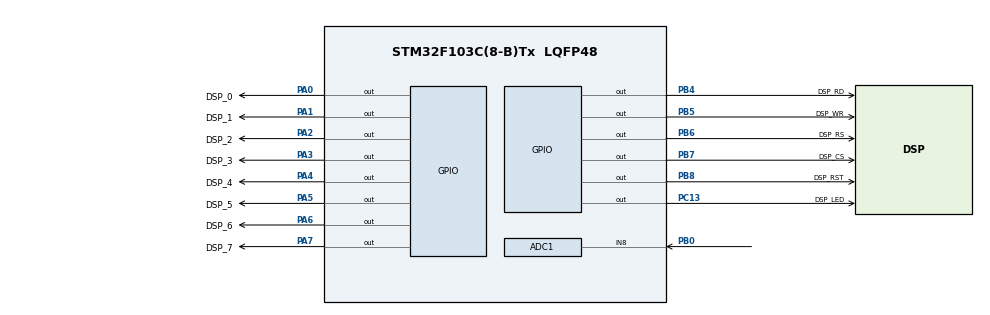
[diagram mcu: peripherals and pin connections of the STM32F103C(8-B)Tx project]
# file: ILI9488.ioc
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ADC1.Channel-0\#ChannelRegularConversion=ADC_CHANNEL_8
ADC1.ExternalTrigConv=ADC_EXTERNALTRIGCONV_T3_TRGO
ADC1.NbrOfConversionFlag=1
ADC1.Rank-0\#ChannelRegularConversion=1
ADC1.SamplingTime-0\#ChannelRegularConversion=ADC_SAMPLETIME_1CYCLE_5
ADC1.master=1
Mcu.Family=STM32F1
Mcu.Name=STM32F103C(8-B)Tx
Mcu.Package=LQFP48
NVIC.PriorityGroup=NVIC_PRIORITYGROUP_4
NVIC.TIM3_IRQn=true\:0\:0\:false\:false\:true
PA0-WKUP.GPIO_Label=DSP_0
PA0-WKUP.GPIO_ModeDefaultOutputPP=GPIO_MODE_OUTPUT_PP
PA0-WKUP.GPIO_Speed=GPIO_SPEED_FREQ_HIGH
PA0-WKUP.PinState=GPIO_PIN_RESET
PA0-WKUP.Signal=GPIO_Output
PA1.GPIO_Label=DSP_1
PA1.GPIO_ModeDefaultOutputPP=GPIO_MODE_OUTPUT_PP
PA1.GPIO_Speed=GPIO_SPEED_FREQ_HIGH
PA1.PinState=GPIO_PIN_RESET
PA1.Signal=GPIO_Output
PA13.Mode=Serial_Wire
PA13.Signal=SYS_JTMS-SWDIO
PA14.Mode=Serial_Wire
PA14.Signal=SYS_JTCK-SWCLK
PA2.GPIO_Label=DSP_2
PA2.GPIO_ModeDefaultOutputPP=GPIO_MODE_OUTPUT_PP
PA2.GPIO_Speed=GPIO_SPEED_FREQ_HIGH
PA2.PinState=GPIO_PIN_RESET
PA2.Signal=GPIO_Output
PA3.GPIO_Label=DSP_3
PA3.GPIO_ModeDefaultOutputPP=GPIO_MODE_OUTPUT_PP
PA3.GPIO_Speed=GPIO_SPEED_FREQ_HIGH
PA3.PinState=GPIO_PIN_RESET
PA3.Signal=GPIO_Output
PA4.GPIO_Label=DSP_4
PA4.GPIO_ModeDefaultOutputPP=GPIO_MODE_OUTPUT_PP
PA4.GPIO_Speed=GPIO_SPEED_FREQ_HIGH
PA4.PinState=GPIO_PIN_RESET
PA4.Signal=GPIO_Output
PA5.GPIO_Label=DSP_5
PA5.GPIO_ModeDefaultOutputPP=GPIO_MODE_OUTPUT_PP
PA5.GPIO_Speed=GPIO_SPEED_FREQ_HIGH
PA5.PinState=GPIO_PIN_RESET
PA5.Signal=GPIO_Output
PA6.GPIO_Label=DSP_6
PA6.GPIO_ModeDefaultOutputPP=GPIO_MODE_OUTPUT_PP
PA6.GPIO_Speed=GPIO_SPEED_FREQ_HIGH
PA6.PinState=GPIO_PIN_RESET
PA6.Signal=GPIO_Output
PA7.GPIO_Label=DSP_7
PA7.GPIO_ModeDefaultOutputPP=GPIO_MODE_OUTPUT_PP
PA7.GPIO_Speed=GPIO_SPEED_FREQ_HIGH
PA7.PinState=GPIO_PIN_RESET
PA7.Signal=GPIO_Output
PB0.Signal=ADCx_IN8
PB4.GPIO_Label=DSP_RD
PB4.GPIO_ModeDefaultOutputPP=GPIO_MODE_OUTPUT_PP
PB4.GPIO_Speed=GPIO_SPEED_FREQ_HIGH
PB4.PinState=GPIO_PIN_RESET
PB4.Signal=GPIO_Output
PB5.GPIO_Label=DSP_WR
PB5.GPIO_ModeDefaultOutputPP=GPIO_MODE_OUTPUT_PP
PB5.GPIO_Speed=GPIO_SPEED_FREQ_HIGH
PB5.PinState=GPIO_PIN_RESET
PB5.Signal=GPIO_Output
PB6.GPIO_Label=DSP_RS
PB6.GPIO_ModeDefaultOutputPP=GPIO_MODE_OUTPUT_PP
PB6.GPIO_Speed=GPIO_SPEED_FREQ_HIGH
PB6.PinState=GPIO_PIN_RESET
PB6.Signal=GPIO_Output
PB7.GPIO_Label=DSP_CS
PB7.GPIO_ModeDefaultOutputPP=GPIO_MODE_OUTPUT_PP
PB7.GPIO_Speed=GPIO_SPEED_FREQ_HIGH
PB7.PinState=GPIO_PIN_RESET
PB7.Signal=GPIO_Output
PB8.GPIO_Label=DSP_RST
PB8.GPIO_ModeDefaultOutputPP=GPIO_MODE_OUTPUT_PP
PB8.GPIO_Speed=GPIO_SPEED_FREQ_HIGH
PB8.PinState=GPIO_PIN_RESET
PB8.Signal=GPIO_Output
PC13-TAMPER-RTC.GPIO_Label=DSP_LED
PC13-TAMPER-RTC.GPIO_ModeDefaultOutputPP=GPIO_MODE_OUTPUT_PP
PC13-TAMPER-RTC.GPIO_Speed=GPIO_SPEED_FREQ_HIGH
PC13-TAMPER-RTC.PinState=GPIO_PIN_RESET
PC13-TAMPER-RTC.Signal=GPIO_Output
PD0-OSC_IN.Mode=HSE-External-Oscillator
PD0-OSC_IN.Signal=RCC_OSC_IN
PD1-OSC_OUT.Mode=HSE-External-Oscillator
PD1-OSC_OUT.Signal=RCC_OSC_OUT
ProjectManager.HeapSize=0x200
ProjectManager.StackSize=0x400
ProjectManager.TargetToolchain=Makefile
RCC.ADCPresc=RCC_ADCPCLK2_DIV6
RCC.AHBFreq_Value=72000000
RCC.APB1CLKDivider=RCC_HCLK_DIV2
RCC.APB1Freq_Value=36000000
RCC.APB1TimFreq_Value=72000000
RCC.APB2Freq_Value=72000000
RCC.APB2TimFreq_Value=72000000
RCC.HCLKFreq_Value=72000000
RCC.PLLMUL=RCC_PLL_MUL9
RCC.PLLSourceVirtual=RCC_PLLSOURCE_HSE
RCC.SYSCLKFreq_VALUE=72000000
RCC.SYSCLKSource=RCC_SYSCLKSOURCE_PLLCLK
RCC.USBFreq_Value=72000000
SH.ADCx_IN8.0=ADC1_IN8,IN8
TIM3.Period=10
TIM3.Prescaler=64-1
TIM3.TIM_MasterOutputTrigger=TIM_TRGO_UPDATE
VP_TIM3_VS_ClockSourceINT.Mode=Internal
board=ILI9488

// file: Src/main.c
/**
  ******************************************************************************
  * File Name          : main.c
  * Description        : Main program body
  ******************************************************************************
  ** This notice applies to any and all portions of this file
  * that are not between comment pairs USER CODE BEGIN and
  * USER CODE END. Other portions of this file, whether
  * inserted by the user or by software development tools
  * are owned by their respective copyright owners.
  *
  * COPYRIGHT(c) 2018 STMicroelectronics
  *
  * Redistribution and use in source and binary forms, with or without modification,
  * are permitted provided that the following conditions are met:
  *   1. Redistributions of source code must retain the above copyright notice,
  *      this list of conditions and the following disclaimer.
  *   2. Redistributions in binary form must reproduce the above copyright notice,
  *      this list of conditions and the following disclaimer in the documentation
  *      and/or other materials provided with the distribution.
  *   3. Neither the name of STMicroelectronics nor the names of its contributors
  *      may be used to endorse or promote products derived from this software
  *      without specific prior written permission.
  *
  * THIS SOFTWARE IS PROVIDED BY THE COPYRIGHT HOLDERS AND CONTRIBUTORS "AS IS"
  * AND ANY EXPRESS OR IMPLIED WARRANTIES, INCLUDING, BUT NOT LIMITED TO, THE
  * IMPLIED WARRANTIES OF MERCHANTABILITY AND FITNESS FOR A PARTICULAR PURPOSE ARE
  * DISCLAIMED. IN NO EVENT SHALL THE COPYRIGHT HOLDER OR CONTRIBUTORS BE LIABLE
  * FOR ANY DIRECT, INDIRECT, INCIDENTAL, SPECIAL, EXEMPLARY, OR CONSEQUENTIAL
  * DAMAGES (INCLUDING, BUT NOT LIMITED TO, PROCUREMENT OF SUBSTITUTE GOODS OR
  * SERVICES; LOSS OF USE, DATA, OR PROFITS; OR BUSINESS INTERRUPTION) HOWEVER
  * CAUSED AND ON ANY THEORY OF LIABILITY, WHETHER IN CONTRACT, STRICT LIABILITY,
  * OR TORT (INCLUDING NEGLIGENCE OR OTHERWISE) ARISING IN ANY WAY OUT OF THE USE
  * OF THIS SOFTWARE, EVEN IF ADVISED OF THE POSSIBILITY OF SUCH DAMAGE.
  *
  ******************************************************************************
  */
#include "main.h"
#include "stm32f1xx_hal.h"
#include "adc.h"
#include "tim.h"
#include "gpio.h"

/* USER CODE BEGIN Includes */
#include <math.h>
#include "tft9488.h"
#include "utoa.h"
// #include "myimage.h"

#define M_PI 3.14159
/* USER CODE END Includes */

/* USER CODE BEGIN PV */
/* Private variables ---------------------------------------------------------*/
extern TIM_HandleTypeDef htim3;
extern uint16_t BACK_COLOR,POINT_COLOR;
extern uint16_t tft_W;
extern uint16_t tft_H;

uint32_t adcResult = 0;
uint32_t max_result = 0;
float real_result[480] = {0};

uint16_t adc_counter = 0;
uint16_t i = 0;

uint16_t buff_clean[480] = {0};
//uint16_t coord_x[480] = {0};
uint16_t buff_ray[480] = {0};

void write_text(uint16_t i);
void write_grid(void);

void fill_buff(uint16_t i)
{
  while(adc_counter < 48) // Пока количество измерений меньше N
  {
    adcResult += HAL_ADC_GetValue(&hadc1); // Сумируем полученные значения ацп
    adc_counter++; // Увеличиваем счетчик измерений
  }

  buff_ray[i] = tft_H-45-adcResult/adc_counter/18; // Вычисляем среднее значение
  real_result[i] = adcResult/adc_counter*0.82; // 3300/4096=0.80566 Вычисляем среднее значение

  // if(real_result[i]<500) real_result[i] = 0;
  // if(real_result[i]>500) real_result[i] -= 500;
  // real_result[i] *= .4; // значение в барах

  adcResult = 0; // Обнуляем значение
  adc_counter = 0; // Обнуляем счетчик измерений
  if(real_result[i]>max_result) max_result = real_result[i]; // save max value
}

void rotate_buff(uint16_t r)
{
    uint16_t tmp;
    for(i = 0; i < r; i++) // scroll buff_ray
    {
      tmp = buff_ray[tft_W-1];
      for(uint16_t i = tft_W-1; i; i--)
      {
        buff_ray[i] = buff_ray[i-1];
      }
      buff_ray[0] = tmp;
    }
}

void write_graph(uint16_t i)
{
  //write_text(i);
  if(i>0 && i < tft_W-0){ // clean old ray
    //tft_draw_point_big(i, buff_clean[i],COLOR_BLACK); //зарисовка предыдущего луча;
    //tft_draw_line_slim(i+1, buff_clean[i+1], i, buff_clean[i], COLOR_BLACK); //зарисовка предыдущего луча;
    tft_draw_dot_line(i+1, buff_clean[i+1], i, buff_clean[i], COLOR_BLACK); //зарисовка предыдущего луча;
  }
  if(i>2 && i < tft_W-2){ // draw new ray
    //tft_draw_point_big(i, buff_ray[i], COLOR_WHITE); //прорисовка текущего луча;
    //tft_draw_line_slim(i, buff_ray[i], i-1, buff_ray[i-1], COLOR_WHITE); //прорисовка текущего луча;
    tft_draw_dot_line(i, buff_ray[i], i-1, buff_ray[i-1], COLOR_WHITE); //прорисовка текущего луча;
  }
  buff_clean[i]=buff_ray[i];
}

void write_grid(void)
{
  for(uint16_t x = 32;x<tft_H-31;x+=8)for(uint16_t i = 16; i<tft_W-15; i+=64)tft_draw_point(i, x, COLOR_GRAYBLUE); //draw vertical dot line
  for(uint16_t x = 32;x<tft_H-31;x+=64)for(uint16_t i = 16; i<tft_W-15; i+=8)tft_draw_point(i, x, COLOR_WHITE); //draw horizontal dot line
}

void write_text(uint16_t i) // for text data
{
  char lbl_real[16] = "mv";
  BACK_COLOR=COLOR_BLUE;
  POINT_COLOR=COLOR_GREEN;
  tft_puts18x32(0,110,(int8_t*)lbl_real,TFT_STRING_MODE_BACKGROUND);

  char real_mv[16];
  utoa((int)real_result[i], real_mv, 10);
  if(real_result[i]<1000)tft_fill(1,62,32,80,BACK_COLOR); //x1 y1 x2 y2
  if(real_result[i]<100) tft_fill(1,44,32,80,BACK_COLOR); //x1 y1 x2 y2
  if(real_result[i]<10)  tft_fill(1,26,32,80,BACK_COLOR); //x1 y1 x2 y2
  tft_puts18x32(0,10,(int8_t*)real_mv,TFT_STRING_MODE_BACKGROUND);
}

/* USER CODE END PV */

void SystemClock_Config(void);

/* USER CODE BEGIN PFP */
/* Private function prototypes -----------------------------------------------*/

/* USER CODE END PFP */

int main(void)
{

  /* MCU Configuration----------------------------------------------------------*/

  /* Reset of all peripherals, Initializes the Flash interface and the Systick. */
  HAL_Init();

  /* Configure the system clock */
  SystemClock_Config();

  /* Initialize all configured peripherals */
  MX_GPIO_Init();
  MX_TIM3_Init();
  MX_ADC1_Init();

  /* USER CODE BEGIN 2 */
  tft_init();
  tft_SetRotation(1);
  tft_clear(COLOR_BLACK);

  tft_draw_rectangle(31,0,0,tft_W,COLOR_RED);
  tft_fill(1,1,30,tft_W-1,COLOR_YELLOW); // x1,y1,x2,y2

  tft_draw_rectangle(tft_H-31,0,tft_H,tft_W,COLOR_RED);
  tft_fill(tft_H-30,1,tft_H-1,tft_W-1,COLOR_YELLOW);

  write_grid(); // draw grid
  write_text(i); // draw label & voltage measurement

  BACK_COLOR=COLOR_RED;
  POINT_COLOR=COLOR_BLUE;
  tft_putchar(tft_W/2,20,'A',TFT_STRING_MODE_NO_BACKGROUND);

  /* USER CODE END 2 */

  /* Infinite loop */
  /* USER CODE BEGIN WHILE */
  HAL_TIM_Base_Init(&htim3);
  HAL_TIM_PeriodElapsedCallback(&htim3);
  HAL_TIM_Base_Start_IT(&htim3); //запустим таймер
  HAL_ADC_Start(&hadc1);//запустим аналогово-цифровое преобразование

  while (1)
  {

  /* USER CODE END WHILE */

  /* USER CODE BEGIN 3 */
    float t, a1, a2;

    t = 3300/2; // порог в миливольтах
    fill_buff(0); a1 = real_result[0];
    fill_buff(0); a2 = real_result[0];

    while (!((a1 < t) && (a2 >= t))) // т.е. было ниже порога, а стало больше или равно - был переход через порог
    {
      a1 = a2;
      fill_buff(0); a2 = real_result[0];
    }

    rotate_buff(5); // scrolling buffer

    for(uint16_t i = 0; i < tft_W; i++) // measurement
    {
      fill_buff(i);
    }

    for(uint16_t i = 0; i < tft_W; i++) // display redraw
    {
      write_graph(i);
    }

    write_grid(); // upgrade grid
    write_text(i); // upgrade label & voltage measurement

  }
  /* USER CODE END 3 */

}

/** System Clock Configuration
*/
void SystemClock_Config(void)
{

  RCC_OscInitTypeDef RCC_OscInitStruct;
  RCC_ClkInitTypeDef RCC_ClkInitStruct;
  RCC_PeriphCLKInitTypeDef PeriphClkInit;

    /**Initializes the CPU, AHB and APB busses clocks
    */
  RCC_OscInitStruct.OscillatorType = RCC_OSCILLATORTYPE_HSE;
  RCC_OscInitStruct.HSEState = RCC_HSE_ON;
  RCC_OscInitStruct.HSEPredivValue = RCC_HSE_PREDIV_DIV1;
  RCC_OscInitStruct.HSIState = RCC_HSI_ON;
  RCC_OscInitStruct.PLL.PLLState = RCC_PLL_ON;
  RCC_OscInitStruct.PLL.PLLSource = RCC_PLLSOURCE_HSE;
  RCC_OscInitStruct.PLL.PLLMUL = RCC_PLL_MUL16; // overclock 128 MHz
  if (HAL_RCC_OscConfig(&RCC_OscInitStruct) != HAL_OK)
  {
    _Error_Handler(__FILE__, __LINE__);
  }

    /**Initializes the CPU, AHB and APB busses clocks
    */
  RCC_ClkInitStruct.ClockType = RCC_CLOCKTYPE_HCLK|RCC_CLOCKTYPE_SYSCLK
                              |RCC_CLOCKTYPE_PCLK1|RCC_CLOCKTYPE_PCLK2;
  RCC_ClkInitStruct.SYSCLKSource = RCC_SYSCLKSOURCE_PLLCLK;
  RCC_ClkInitStruct.AHBCLKDivider = RCC_SYSCLK_DIV1;
  RCC_ClkInitStruct.APB1CLKDivider = RCC_HCLK_DIV2;
  RCC_ClkInitStruct.APB2CLKDivider = RCC_HCLK_DIV1;

  if (HAL_RCC_ClockConfig(&RCC_ClkInitStruct, FLASH_LATENCY_2) != HAL_OK)
  {
    _Error_Handler(__FILE__, __LINE__);
  }

  PeriphClkInit.PeriphClockSelection = RCC_PERIPHCLK_ADC;
  PeriphClkInit.AdcClockSelection = RCC_ADCPCLK2_DIV6;
  if (HAL_RCCEx_PeriphCLKConfig(&PeriphClkInit) != HAL_OK)
  {
    _Error_Handler(__FILE__, __LINE__);
  }

    /**Configure the Systick interrupt time
    */
  HAL_SYSTICK_Config(HAL_RCC_GetHCLKFreq()/1000);

    /**Configure the Systick
    */
  HAL_SYSTICK_CLKSourceConfig(SYSTICK_CLKSOURCE_HCLK);

  /* SysTick_IRQn interrupt configuration */
  HAL_NVIC_SetPriority(SysTick_IRQn, 0, 0);
}

void _Error_Handler(char * file, int line)
{
  while(1)
  {
  }
}

/************************ (C) COPYRIGHT STMicroelectronics *****END OF FILE****/
